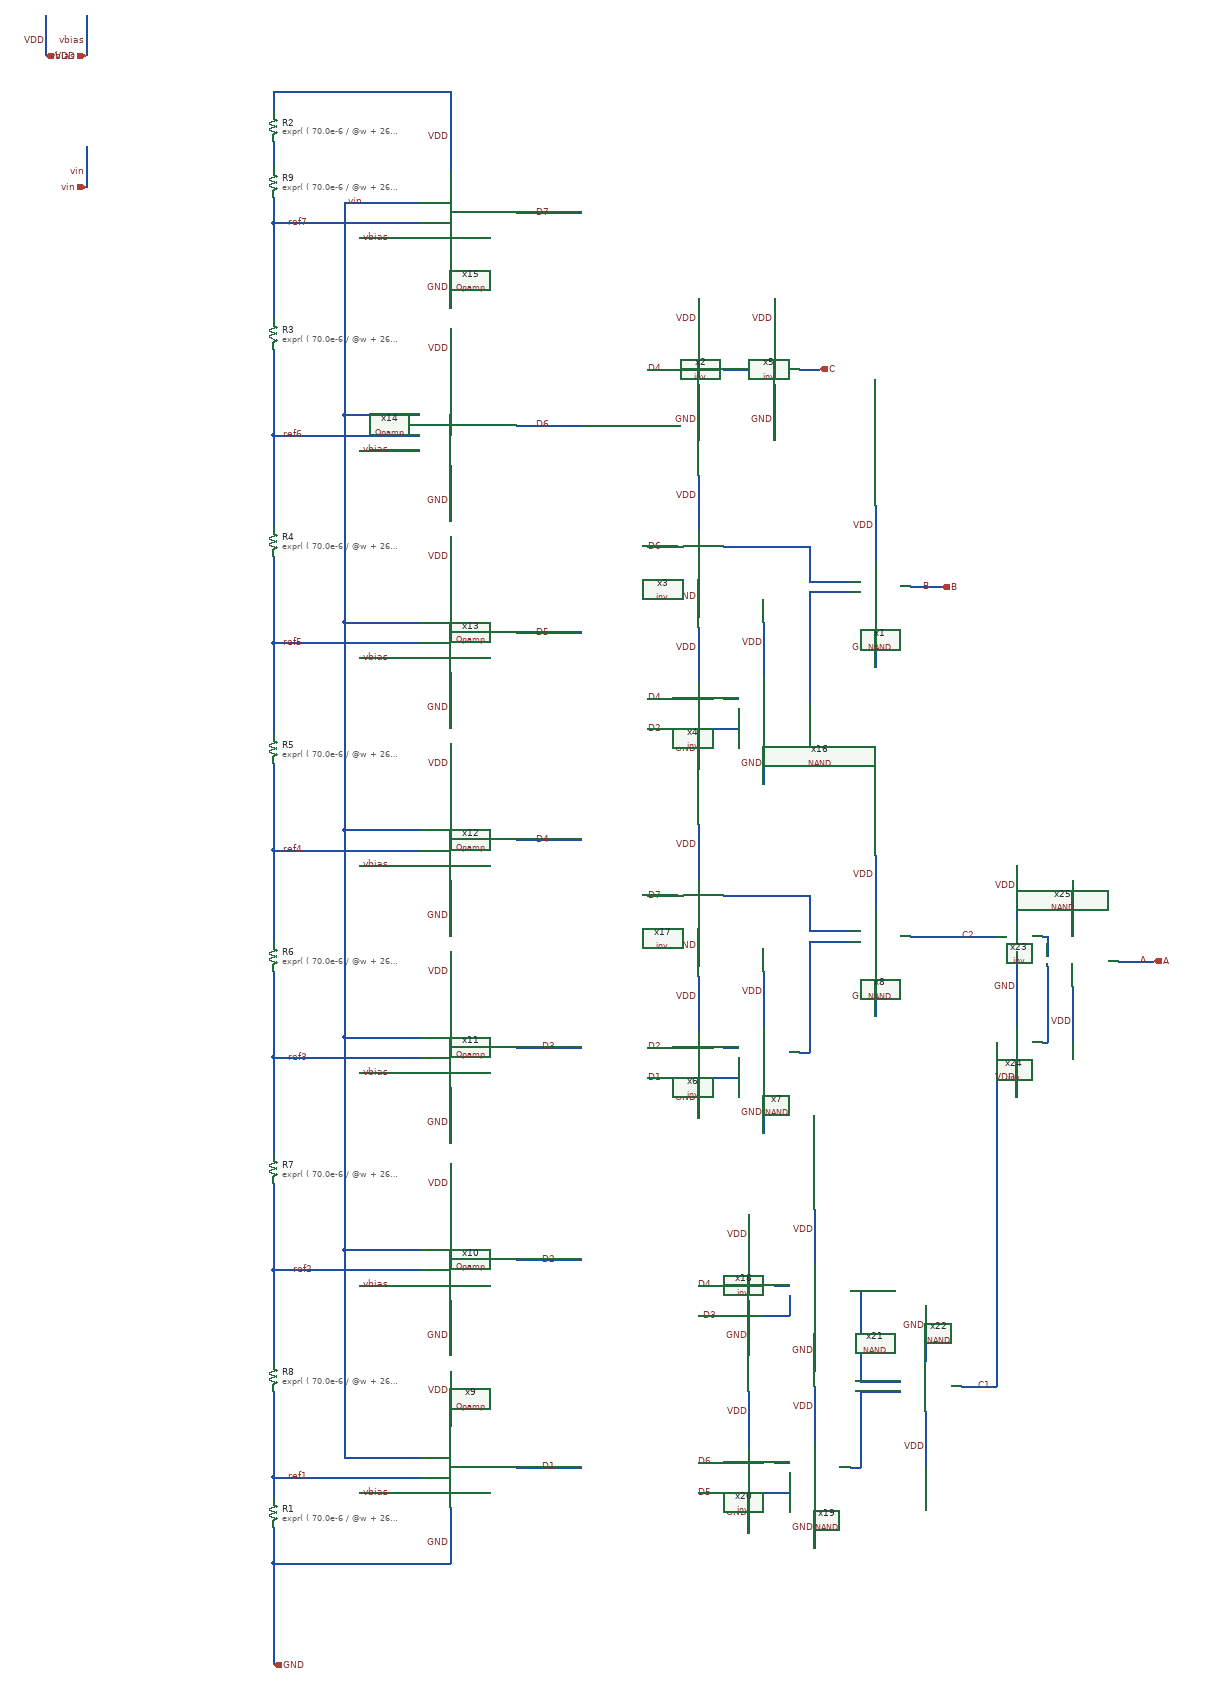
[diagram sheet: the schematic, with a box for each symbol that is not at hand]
v {xschem version=3.4.6 file_version=1.2}
G {}
K {}
V {}
S {}
E {}
N 850 -4380 850 -4270 {lab=VDD}
N 850 -4110 850 -4000 {lab=GND}
N 670 -4140 790 -4140 {lab=vbias}
N 980 -4190 1110 -4190 {lab=D1}
N 850 -4790 850 -4680 {lab=VDD}
N 850 -4520 850 -4410 {lab=GND}
N 670 -4550 790 -4550 {lab=vbias}
N 980 -4600 1110 -4600 {lab=D2}
N 850 -5210 850 -5100 {lab=VDD}
N 850 -4940 850 -4830 {lab=GND}
N 670 -4970 790 -4970 {lab=vbias}
N 980 -5020 1110 -5020 {lab=D3}
N 850 -5620 850 -5510 {lab=VDD}
N 850 -5350 850 -5240 {lab=GND}
N 670 -5380 790 -5380 {lab=vbias}
N 980 -5430 1110 -5430 {lab=D4}
N 850 -6030 850 -5920 {lab=VDD}
N 850 -5760 850 -5650 {lab=GND}
N 670 -5790 790 -5790 {lab=vbias}
N 980 -5840 1110 -5840 {lab=D5}
N 850 -6440 850 -6330 {lab=VDD}
N 850 -6170 850 -6060 {lab=GND}
N 670 -6200 790 -6200 {lab=vbias}
N 980 -6250 1110 -6250 {lab=D6}
N 850 -6590 850 -6480 {lab=GND}
N 670 -6620 790 -6620 {lab=vbias}
N 980 -6670 1110 -6670 {lab=D7}
N 640 -4210 790 -4210 {lab=vin}
N 640 -4620 640 -4210 {lab=vin}
N 640 -4620 790 -4620 {lab=vin}
N 640 -5040 640 -4620 {lab=vin}
N 640 -5040 790 -5040 {lab=vin}
N 640 -5450 640 -5040 {lab=vin}
N 640 -5450 790 -5450 {lab=vin}
N 640 -5860 640 -5450 {lab=vin}
N 640 -5860 790 -5860 {lab=vin}
N 640 -6270 640 -5860 {lab=vin}
N 640 -6270 790 -6270 {lab=vin}
N 640 -6690 640 -6270 {lab=vin}
N 640 -6690 790 -6690 {lab=vin}
N 500 -6650 790 -6650 {lab=ref7}
N 500 -6650 500 -6460 {lab=ref7}
N 500 -6230 790 -6230 {lab=ref6}
N 500 -6230 500 -6050 {lab=ref6}
N 500 -5990 500 -5820 {lab=ref5}
N 500 -5820 790 -5820 {lab=ref5}
N 500 -6400 500 -6230 {lab=ref6}
N 500 -5820 500 -5640 {lab=ref5}
N 500 -5580 500 -5410 {lab=ref4}
N 500 -5410 790 -5410 {lab=ref4}
N 500 -5410 500 -5230 {lab=ref4}
N 500 -5170 500 -5000 {lab=ref3}
N 500 -5000 790 -5000 {lab=ref3}
N 500 -4580 790 -4580 {lab=ref2}
N 500 -5000 500 -4810 {lab=ref3}
N 500 -4170 790 -4170 {lab=ref1}
N 500 -4580 500 -4400 {lab=ref2}
N 500 -4750 500 -4580 {lab=ref2}
N 500 -4340 500 -4170 {lab=ref1}
N 50 -7060 50 -6980 {lab=VDD}
N 130 -7060 130 -6980 {lab=vbias}
N 130 -6800 130 -6720 {lab=vin}
N 850 -6910 850 -6750 {lab=VDD}
N 500 -6910 850 -6910 {lab=VDD}
N 500 -6910 500 -6870 {lab=VDD}
N 500 -4170 500 -4130 {lab=ref1}
N 500 -6810 500 -6760 {lab=#net1}
N 500 -6700 500 -6650 {lab=ref7}
N 1340 -5680 1340 -5570 {lab=GND}
N 1340 -5850 1340 -5740 {lab=VDD}
N 1240 -6010 1300 -6010 {lab=D6}
N 1240 -5710 1300 -5710 {lab=D4}
N 1240 -5650 1420 -5650 {lab=D2}
N 1470 -5650 1470 -5540 {lab=GND}
N 1470 -5860 1470 -5750 {lab=VDD}
N 1760 -5930 1820 -5930 {lab=B}
N 1690 -6090 1690 -5980 {lab=VDD}
N 1690 -5880 1690 -5770 {lab=GND}
N 1390 -5710 1420 -5710 {lab=#net2}
N 1420 -5690 1420 -5650 {lab=D2}
N 1560 -5920 1560 -5700 {lab=#net3}
N 1560 -5920 1640 -5920 {lab=#net3}
N 1340 -5980 1340 -5870 {lab=GND}
N 1340 -6150 1340 -6040 {lab=VDD}
N 1560 -6010 1560 -5940 {lab=#net4}
N 1390 -6010 1560 -6010 {lab=#net4}
N 1560 -5940 1640 -5940 {lab=#net4}
N 1340 -4990 1340 -4880 {lab=GND}
N 1340 -5160 1340 -5050 {lab=VDD}
N 1240 -5320 1300 -5320 {lab=D7}
N 1240 -5020 1300 -5020 {lab=D2}
N 1240 -4960 1420 -4960 {lab=D1}
N 1470 -4960 1470 -4850 {lab=GND}
N 1470 -5170 1470 -5060 {lab=VDD}
N 1760 -5240 1930 -5240 {lab=C2}
N 1690 -5400 1690 -5290 {lab=VDD}
N 1690 -5190 1690 -5080 {lab=GND}
N 1390 -5020 1420 -5020 {lab=#net5}
N 1560 -5230 1560 -5010 {lab=#net6}
N 1560 -5230 1640 -5230 {lab=#net6}
N 1340 -5290 1340 -5180 {lab=GND}
N 1340 -5460 1340 -5350 {lab=VDD}
N 1560 -5320 1560 -5250 {lab=#net7}
N 1390 -5320 1560 -5320 {lab=#net7}
N 1560 -5250 1640 -5250 {lab=#net7}
N 1540 -5010 1560 -5010 {lab=#net6}
N 1440 -4520 1440 -4410 {lab=GND}
N 1440 -4690 1440 -4580 {lab=VDD}
N 1340 -4550 1400 -4550 {lab=D4}
N 1340 -4490 1520 -4490 {lab=D3}
N 1570 -4490 1570 -4380 {lab=GND}
N 1570 -4700 1570 -4590 {lab=VDD}
N 1490 -4550 1520 -4550 {lab=#net8}
N 1440 -4170 1440 -4060 {lab=GND}
N 1440 -4340 1440 -4230 {lab=VDD}
N 1340 -4200 1400 -4200 {lab=D6}
N 1340 -4140 1520 -4140 {lab=D5}
N 1570 -4140 1570 -4030 {lab=GND}
N 1570 -4350 1570 -4240 {lab=VDD}
N 1490 -4200 1520 -4200 {lab=#net9}
N 1790 -4510 1790 -4400 {lab=GND}
N 1790 -4300 1790 -4190 {lab=VDD}
N 1660 -4340 1740 -4340 {lab=#net10}
N 1660 -4360 1740 -4360 {lab=#net11}
N 1660 -4540 1660 -4360 {lab=#net11}
N 1660 -4340 1660 -4190 {lab=#net10}
N 1640 -4540 1660 -4540 {lab=#net11}
N 1640 -4190 1660 -4190 {lab=#net10}
N 1860 -4350 1930 -4350 {lab=C1}
N 1420 -5000 1420 -4960 {lab=D1}
N 1520 -4530 1520 -4490 {lab=D3}
N 1520 -4180 1520 -4140 {lab=D5}
N 2080 -5140 2080 -5030 {lab=VDD}
N 2080 -5350 2080 -5240 {lab=GND}
N 2170 -5190 2240 -5190 {lab=A}
N 2020 -5240 2030 -5240 {lab=#net12}
N 2030 -5240 2030 -5200 {lab=#net12}
N 2020 -5030 2030 -5030 {lab=#net13}
N 2030 -5180 2030 -5030 {lab=#net13}
N 1970 -5380 1970 -5270 {lab=VDD}
N 1930 -5030 1930 -4350 {lab=C1}
N 1970 -5000 1970 -4920 {lab=VDD}
N 1970 -5210 1970 -5060 {lab=GND}
N 500 -4000 850 -4000 {lab=GND}
N 500 -4070 500 -4000 {lab=GND}
N 500 -4000 500 -3800 {lab=GND}
N 1240 -6360 1300 -6360 {lab=D4}
N 1340 -6330 1340 -6220 {lab=GND}
N 1340 -6500 1340 -6390 {lab=VDD}
N 1390 -6360 1450 -6360 {lab=#net14}
N 1490 -6330 1490 -6220 {lab=GND}
N 1490 -6500 1490 -6390 {lab=VDD}
N 1540 -6360 1580 -6360 {lab=C}
C {Opamp.sym} 830 -4190 0 0 {name=x9}
C {lab_wire.sym} 850 -4340 0 0 {name=p25 sig_type=std_logic lab=VDD}
C {lab_wire.sym} 850 -4040 0 0 {name=p26 sig_type=std_logic lab=GND}
C {lab_wire.sym} 730 -4140 0 0 {name=p27 sig_type=std_logic lab=vbias}
C {Opamp.sym} 830 -4600 0 0 {name=x10}
C {lab_wire.sym} 850 -4750 0 0 {name=p28 sig_type=std_logic lab=VDD}
C {lab_wire.sym} 850 -4450 0 0 {name=p29 sig_type=std_logic lab=GND}
C {lab_wire.sym} 730 -4550 0 0 {name=p30 sig_type=std_logic lab=vbias}
C {Opamp.sym} 830 -5020 0 0 {name=x11}
C {lab_wire.sym} 850 -5170 0 0 {name=p31 sig_type=std_logic lab=VDD}
C {lab_wire.sym} 850 -4870 0 0 {name=p32 sig_type=std_logic lab=GND}
C {lab_wire.sym} 730 -4970 0 0 {name=p33 sig_type=std_logic lab=vbias}
C {Opamp.sym} 830 -5430 0 0 {name=x12}
C {lab_wire.sym} 850 -5580 0 0 {name=p34 sig_type=std_logic lab=VDD}
C {lab_wire.sym} 850 -5280 0 0 {name=p35 sig_type=std_logic lab=GND}
C {lab_wire.sym} 730 -5380 0 0 {name=p36 sig_type=std_logic lab=vbias}
C {Opamp.sym} 830 -5840 0 0 {name=x13}
C {lab_wire.sym} 850 -5990 0 0 {name=p37 sig_type=std_logic lab=VDD}
C {lab_wire.sym} 850 -5690 0 0 {name=p38 sig_type=std_logic lab=GND}
C {lab_wire.sym} 730 -5790 0 0 {name=p39 sig_type=std_logic lab=vbias}
C {Opamp.sym} 830 -6250 0 0 {name=x14}
C {lab_wire.sym} 850 -6400 0 0 {name=p40 sig_type=std_logic lab=VDD}
C {lab_wire.sym} 850 -6100 0 0 {name=p41 sig_type=std_logic lab=GND
}
C {lab_wire.sym} 730 -6200 0 0 {name=p42 sig_type=std_logic lab=vbias}
C {Opamp.sym} 830 -6670 0 0 {name=x15}
C {lab_wire.sym} 850 -6820 0 0 {name=p43 sig_type=std_logic lab=VDD}
C {lab_wire.sym} 850 -6520 0 0 {name=p44 sig_type=std_logic lab=GND
}
C {lab_wire.sym} 730 -6620 0 0 {name=p45 sig_type=std_logic lab=vbias}
C {lab_wire.sym} 50 -7010 0 0 {name=p50 sig_type=std_logic lab=VDD}
C {lab_wire.sym} 130 -7010 0 0 {name=p51 sig_type=std_logic lab=vbias}
C {lab_wire.sym} 130 -6750 0 0 {name=p53 sig_type=std_logic lab=vin}
C {lab_wire.sym} 570 -4170 0 0 {name=p60 sig_type=std_logic lab=ref1}
C {lab_wire.sym} 580 -4580 0 0 {name=p61 sig_type=std_logic lab=ref2}
C {lab_wire.sym} 570 -5000 0 0 {name=p62 sig_type=std_logic lab=ref3}
C {lab_wire.sym} 570 -6650 0 0 {name=p63 sig_type=std_logic lab=ref7}
C {lab_wire.sym} 560 -6230 0 0 {name=p64 sig_type=std_logic lab=ref6}
C {lab_wire.sym} 560 -5820 0 0 {name=p65 sig_type=std_logic lab=ref5}
C {lab_wire.sym} 560 -5410 0 0 {name=p66 sig_type=std_logic lab=ref4}
C {lab_wire.sym} 680 -6690 0 0 {name=p46 sig_type=std_logic lab=vin}
C {lab_wire.sym} 1060 -4190 0 0 {name=p1 sig_type=std_logic lab=D1}
C {lab_wire.sym} 1060 -4600 0 0 {name=p2 sig_type=std_logic lab=D2}
C {lab_wire.sym} 1060 -5020 0 0 {name=p3 sig_type=std_logic lab=D3}
C {lab_wire.sym} 1050 -5430 0 0 {name=p4 sig_type=std_logic lab=D4}
C {lab_wire.sym} 1050 -5840 0 0 {name=p5 sig_type=std_logic lab=D5}
C {lab_wire.sym} 1050 -6250 0 0 {name=p6 sig_type=std_logic lab=D6}
C {lab_wire.sym} 1050 -6670 0 0 {name=p7 sig_type=std_logic lab=D7}
C {lab_wire.sym} 1340 -5610 0 0 {name=p21 sig_type=std_logic lab=GND
}
C {lab_wire.sym} 1340 -5810 0 0 {name=p22 sig_type=std_logic lab=VDD}
C {lab_wire.sym} 1270 -6010 0 0 {name=p48 sig_type=std_logic lab=D6}
C {lab_wire.sym} 1270 -5710 0 0 {name=p49 sig_type=std_logic lab=D4}
C {lab_wire.sym} 1270 -5650 0 0 {name=p52 sig_type=std_logic lab=D2}
C {lab_wire.sym} 1800 -5930 0 0 {name=p54 sig_type=std_logic lab=B}
C {lab_wire.sym} 1470 -5580 0 0 {name=p73 sig_type=std_logic lab=GND
}
C {lab_wire.sym} 1470 -5820 0 0 {name=p74 sig_type=std_logic lab=VDD}
C {lab_wire.sym} 1690 -6050 0 0 {name=p79 sig_type=std_logic lab=VDD}
C {lab_wire.sym} 1690 -5810 0 0 {name=p80 sig_type=std_logic lab=GND
}
C {inv.sym} 1380 -5620 0 0 {name=x4}
C {NAND.sym} 1540 -5610 0 0 {name=x16}
C {NAND.sym} 1760 -5840 0 0 {name=x1}
C {lab_wire.sym} 1340 -5910 0 0 {name=p19 sig_type=std_logic lab=GND
}
C {lab_wire.sym} 1340 -6110 0 0 {name=p20 sig_type=std_logic lab=VDD}
C {inv.sym} 1380 -5920 0 0 {name=x3}
C {lab_wire.sym} 1340 -4920 0 0 {name=p14 sig_type=std_logic lab=GND
}
C {lab_wire.sym} 1340 -5120 0 0 {name=p15 sig_type=std_logic lab=VDD}
C {lab_wire.sym} 1270 -5320 0 0 {name=p16 sig_type=std_logic lab=D7}
C {lab_wire.sym} 1270 -5020 0 0 {name=p17 sig_type=std_logic lab=D2}
C {lab_wire.sym} 1270 -4960 0 0 {name=p18 sig_type=std_logic lab=D1}
C {lab_wire.sym} 1470 -4890 0 0 {name=p24 sig_type=std_logic lab=GND
}
C {lab_wire.sym} 1470 -5130 0 0 {name=p47 sig_type=std_logic lab=VDD}
C {lab_wire.sym} 1690 -5360 0 0 {name=p55 sig_type=std_logic lab=VDD}
C {lab_wire.sym} 1690 -5120 0 0 {name=p56 sig_type=std_logic lab=GND
}
C {inv.sym} 1380 -4930 0 0 {name=x6}
C {lab_wire.sym} 1340 -5220 0 0 {name=p57 sig_type=std_logic lab=GND
}
C {lab_wire.sym} 1340 -5420 0 0 {name=p58 sig_type=std_logic lab=VDD}
C {inv.sym} 1380 -5230 0 0 {name=x17}
C {lab_wire.sym} 1440 -4450 0 0 {name=p59 sig_type=std_logic lab=GND
}
C {lab_wire.sym} 1440 -4650 0 0 {name=p67 sig_type=std_logic lab=VDD}
C {lab_wire.sym} 1370 -4550 0 0 {name=p68 sig_type=std_logic lab=D4}
C {lab_wire.sym} 1380 -4490 0 0 {name=p69 sig_type=std_logic lab=D3}
C {lab_wire.sym} 1570 -4420 0 0 {name=p70 sig_type=std_logic lab=GND
}
C {lab_wire.sym} 1570 -4660 0 0 {name=p71 sig_type=std_logic lab=VDD}
C {inv.sym} 1480 -4460 0 0 {name=x18}
C {lab_wire.sym} 1440 -4100 0 0 {name=p72 sig_type=std_logic lab=GND
}
C {lab_wire.sym} 1440 -4300 0 0 {name=p75 sig_type=std_logic lab=VDD}
C {lab_wire.sym} 1370 -4200 0 0 {name=p76 sig_type=std_logic lab=D6}
C {lab_wire.sym} 1370 -4140 0 0 {name=p77 sig_type=std_logic lab=D5
}
C {lab_wire.sym} 1570 -4070 0 0 {name=p78 sig_type=std_logic lab=GND
}
C {lab_wire.sym} 1570 -4310 0 0 {name=p81 sig_type=std_logic lab=VDD}
C {inv.sym} 1480 -4110 0 0 {name=x20}
C {lab_wire.sym} 1790 -4470 0 0 {name=p83 sig_type=std_logic lab=GND}
C {lab_wire.sym} 1790 -4230 0 0 {name=p84 sig_type=std_logic lab=VDD
}
C {NAND.sym} 1540 -4920 0 0 {name=x7}
C {NAND.sym} 1640 -4100 0 0 {name=x19}
C {NAND.sym} 1640 -4450 0 0 {name=x21}
C {NAND.sym} 1760 -5150 0 0 {name=x8}
C {NAND.sym} 1860 -4440 2 1 {name=x22}
C {lab_wire.sym} 1890 -5240 0 0 {name=p23 sig_type=std_logic lab=C2}
C {lab_wire.sym} 1920 -4350 0 0 {name=p82 sig_type=std_logic lab=C1}
C {lab_wire.sym} 2080 -5070 0 0 {name=p85 sig_type=std_logic lab=VDD
}
C {lab_wire.sym} 2080 -5310 0 0 {name=p86 sig_type=std_logic lab=GND}
C {lab_wire.sym} 2230 -5190 0 0 {name=p87 sig_type=std_logic lab=A}
C {inv.sym} 2010 -5150 0 0 {name=x23}
C {inv.sym} 2010 -5120 2 1 {name=x24}
C {NAND.sym} 2150 -5280 2 1 {name=x25}
C {lab_wire.sym} 1970 -5340 0 0 {name=p89 sig_type=std_logic lab=VDD}
C {lab_wire.sym} 1970 -5140 0 0 {name=p88 sig_type=std_logic lab=GND
}
C {lab_wire.sym} 1970 -4960 0 0 {name=p90 sig_type=std_logic lab=VDD}
C {iopin.sym} 50 -6980 0 1 {name=p92 lab=VDD}
C {iopin.sym} 500 -3800 0 1 {name=p93 lab=GND}
C {ipin.sym} 130 -6980 0 0 {name=p94 lab=vbias}
C {ipin.sym} 130 -6720 0 0 {name=p96 lab=vin}
C {opin.sym} 1820 -5930 0 0 {name=p91 lab=B}
C {opin.sym} 2240 -5190 0 0 {name=p97 lab=A}
C {opin.sym} 1580 -6360 0 0 {name=p8 lab=C}
C {lab_wire.sym} 1270 -6360 0 0 {name=p9 sig_type=std_logic lab=D4}
C {lab_wire.sym} 1340 -6260 0 0 {name=p10 sig_type=std_logic lab=GND
}
C {lab_wire.sym} 1340 -6460 0 0 {name=p11 sig_type=std_logic lab=VDD}
C {inv.sym} 1380 -6270 0 0 {name=x2}
C {lab_wire.sym} 1490 -6260 0 0 {name=p13 sig_type=std_logic lab=GND
}
C {lab_wire.sym} 1490 -6460 0 0 {name=p95 sig_type=std_logic lab=VDD}
C {inv.sym} 1530 -6270 0 0 {name=x5}
C {sg13g2_pr/rppd.sym} 500 -4100 0 0 {name=R1
w=0.5e-6
l=4e-6
model=rppd
body=GND
spiceprefix=X
b=0
m=1
value="expr(  ( 70.0e-6 / @w + 260.0 * ( (@b + 1)* @l + ( 1.081*( @w + 6.0e-9 ) + 0.18e-6 )*@b ) / ( @w + 6.0e-9 ) ) / @m  )"
}
C {sg13g2_pr/rppd.sym} 500 -4370 0 0 {name=R8
w=0.5e-6
l=2e-6
model=rppd
body=GND
spiceprefix=X
b=0
m=1
value="expr(  ( 70.0e-6 / @w + 260.0 * ( (@b + 1)* @l + ( 1.081*( @w + 6.0e-9 ) + 0.18e-6 )*@b ) / ( @w + 6.0e-9 ) ) / @m  )"
}
C {sg13g2_pr/rppd.sym} 500 -4780 0 0 {name=R7
w=0.5e-6
l=2e-6
model=rppd
body=GND
spiceprefix=X
b=0
m=1
value="expr(  ( 70.0e-6 / @w + 260.0 * ( (@b + 1)* @l + ( 1.081*( @w + 6.0e-9 ) + 0.18e-6 )*@b ) / ( @w + 6.0e-9 ) ) / @m  )"
}
C {sg13g2_pr/rppd.sym} 500 -5200 0 0 {name=R6
w=0.5e-6
l=2e-6
model=rppd
body=GND
spiceprefix=X
b=0
m=1
value="expr(  ( 70.0e-6 / @w + 260.0 * ( (@b + 1)* @l + ( 1.081*( @w + 6.0e-9 ) + 0.18e-6 )*@b ) / ( @w + 6.0e-9 ) ) / @m  )"
}
C {sg13g2_pr/rppd.sym} 500 -5610 0 0 {name=R5
w=0.5e-6
l=2e-6
model=rppd
body=GND
spiceprefix=X
b=0
m=1
value="expr(  ( 70.0e-6 / @w + 260.0 * ( (@b + 1)* @l + ( 1.081*( @w + 6.0e-9 ) + 0.18e-6 )*@b ) / ( @w + 6.0e-9 ) ) / @m  )"
}
C {sg13g2_pr/rppd.sym} 500 -6020 0 0 {name=R4
w=0.5e-6
l=2e-6
model=rppd
body=GND
spiceprefix=X
b=0
m=1
value="expr(  ( 70.0e-6 / @w + 260.0 * ( (@b + 1)* @l + ( 1.081*( @w + 6.0e-9 ) + 0.18e-6 )*@b ) / ( @w + 6.0e-9 ) ) / @m  )"
}
C {sg13g2_pr/rppd.sym} 500 -6430 0 0 {name=R3
w=0.5e-6
l=2e-6
model=rppd
body=GND
spiceprefix=X
b=0
m=1
value="expr(  ( 70.0e-6 / @w + 260.0 * ( (@b + 1)* @l + ( 1.081*( @w + 6.0e-9 ) + 0.18e-6 )*@b ) / ( @w + 6.0e-9 ) ) / @m  )"
}
C {sg13g2_pr/rppd.sym} 500 -6840 0 0 {name=R2
w=0.5e-6
l=2e-6
model=rppd
body=GND
spiceprefix=X
b=0
m=1
value="expr(  ( 70.0e-6 / @w + 260.0 * ( (@b + 1)* @l + ( 1.081*( @w + 6.0e-9 ) + 0.18e-6 )*@b ) / ( @w + 6.0e-9 ) ) / @m  )"
}
C {sg13g2_pr/rppd.sym} 500 -6730 0 0 {name=R9
w=0.5e-6
l=2e-6
model=rppd
body=GND
spiceprefix=X
b=0
m=1
value="expr(  ( 70.0e-6 / @w + 260.0 * ( (@b + 1)* @l + ( 1.081*( @w + 6.0e-9 ) + 0.18e-6 )*@b ) / ( @w + 6.0e-9 ) ) / @m  )"
}
